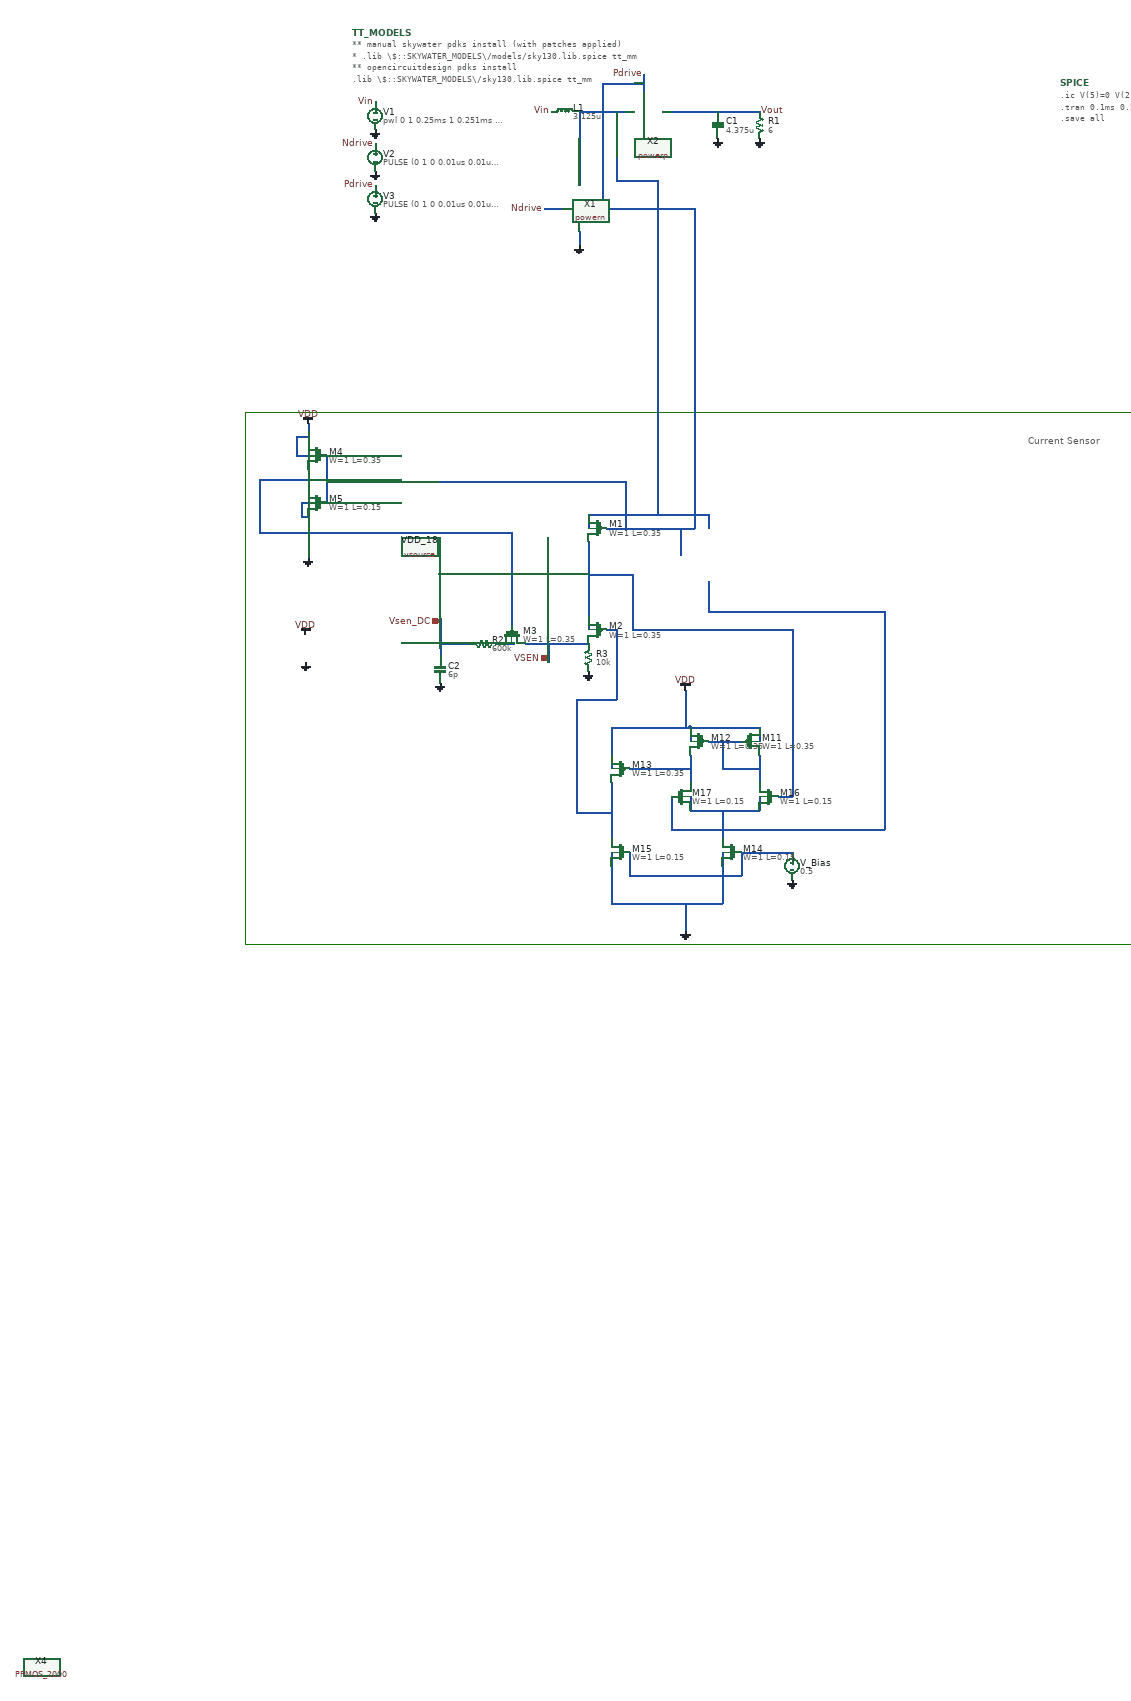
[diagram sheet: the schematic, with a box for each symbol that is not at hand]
v {xschem version=3.0.0 file_version=1.2 }
G {}
K {}
V {}
S {}
E {}
L 4 -330 1910 1650 1910 {}
L 4 1650 760 1650 1910 {}
L 4 -330 760 1650 760 {}
L 4 -330 760 -330 1910 {}
T {Current Sensor} 1360 810 0 0 0.6 0.6 {}
N 390 110 390 210 { lab=#net1}
N 690 110 780 110 { lab=Vout}
N 390 210 390 270 { lab=#net1}
N 390 110 490 110 { lab=#net1}
N 570 110 690 110 { lab=Vout}
N 390 370 390 400 { lab=GND}
N 530 30 530 70 { lab=Pdrive}
N 315 320 355 320 { lab=Ndrive}
N 440 50 530 50 { lab=Pdrive}
N 440 50 440 320 { lab=Pdrive}
N 440 320 550 320 { lab=Pdrive}
N 470 110 470 260 { lab=#net1}
N 470 260 550 260 { lab=#net1}
N 410 1040 410 1140 { lab=#net2}
N 450 1010 640 1010 { lab=Pdrive}
N 410 1140 410 1185 { lab=#net2}
N 410 1185 410 1200 { lab=#net2}
N 450 1230 455 1230 { lab=#net3}
N 275 1260 410 1260 { lab=VSEN}
N 90 1265 90 1285 { lab=Vsen_DC}
N 90 1260 155 1260 { lab=Vsen_DC}
N 90 1260 90 1270 { lab=Vsen_DC}
N 90 1205 90 1265 { lab=Vsen_DC}
N 325 1260 325 1300 { lab=VSEN}
N 490 910 490 1010 { lab=Pdrive}
N -155 910 490 910 { lab=Pdrive}
N -300 905 -195 905 { lab=#net4}
N -300 905 -300 1020 { lab=#net4}
N -300 1020 245 1020 { lab=#net4}
N 245 1020 245 1220 { lab=#net4}
N -195 985 -195 1075 { lab=GND}
N 670 1125 670 1190 { lab=#net5}
N 640 740 640 1010 { lab=Pdrive}
N 410 980 410 1010 { lab=#net1}
N 410 1200 410 1230 { lab=#net2}
N 210 1260 250 1260 { lab=#net6}
N -210 955 -192.5 955 { lab=GND}
N -210 955 -210 985 { lab=GND}
N -210 985 -195 985 { lab=GND}
N -220 852.5 -190 852.5 { lab=VDD}
N -220 812.5 -220 852.5 { lab=VDD}
N -220 812.5 -195 812.5 { lab=VDD}
N -195 882.5 -195 925 { lab=#net4}
N -155 852.5 -155 955 { lab=Pdrive}
N -195 785 -195 812.5 { lab=VDD}
N -195 802.5 -195 822.5 { lab=VDD}
N 610 1010 610 1070 { lab=Pdrive}
N 410 980 670 980 { lab=#net1}
N 670 980 670 1010 { lab=#net1}
N 560 380 560 980 { lab=#net1}
N 640 320 640 740 { lab=Pdrive}
N 550 320 640 320 { lab=Pdrive}
N 560 260 560 380 { lab=#net1}
N 550 260 560 260 { lab=#net1}
N 670 1470 740 1470 { lab=#net7}
N 630 1440 780 1440 { lab=VDD}
N 780 1500 780 1560 { lab=#net7}
N 630 1500 630 1560 { lab=#net8}
N 630 1620 780 1620 { lab=#net9}
N 700 1530 780 1530 { lab=#net7}
N 700 1470 700 1530 { lab=#net7}
N 700 1620 700 1680 { lab=#net9}
N 460 1440 630 1440 { lab=VDD}
N 460 1440 460 1500 { lab=VDD}
N 500 1530 630 1530 { lab=#net8}
N 460 1560 460 1680 { lab=#net3}
N 740 1710 740 1760 { lab=#net10}
N 500 1760 740 1760 { lab=#net10}
N 500 1710 500 1760 { lab=#net10}
N 740 1710 820 1710 { lab=#net10}
N 620 1360 620 1440 { lab=VDD}
N 700 1740 700 1820 { lab=GND}
N 460 1820 700 1820 { lab=GND}
N 460 1740 460 1820 { lab=GND}
N 620 1820 620 1880 { lab=GND}
N 820 1710 850 1710 { lab=#net10}
N 590 1590 590 1660 { lab=#net5}
N 590 1660 820 1660 { lab=#net5}
N 820 1660 850 1660 { lab=#net5}
N 820 1590 850 1590 { lab=#net2}
N 780 1440 780 1470 { lab=VDD}
N 630 1440 630 1470 { lab=VDD}
N 460 1710 460 1740 { lab=GND}
N 700 1710 700 1740 { lab=GND}
N 780 1590 780 1620 { lab=#net9}
N 630 1590 630 1620 { lab=#net9}
N 385 1625 460 1625 { lab=#net3}
N 460 1500 460 1530 { lab=VDD}
N 850 1660 1050 1660 { lab=#net5}
N 1050 1190 1050 1660 { lab=#net5}
N 670 1190 1050 1190 { lab=#net5}
N 850 1230 850 1590 { lab=#net2}
N 385 1380 385 1625 { lab=#net3}
N 385 1380 470 1380 { lab=#net3}
N 470 1230 470 1380 { lab=#net3}
N 455 1230 470 1230 { lab=#net3}
N 505 1230 850 1230 { lab=#net2}
N 505 1110 505 1230 { lab=#net2}
N 410 1110 505 1110 { lab=#net2}
C {devices/code.sym} -100 -60 0 0 {name=TT_MODELS
only_toplevel=true
format="tcleval(@value )"
value="** manual skywater pdks install (with patches applied)
* .lib \\\\$::SKYWATER_MODELS\\\\/models/sky130.lib.spice tt_mm

** opencircuitdesign pdks install
.lib \\\\$::SKYWATER_MODELS\\\\/sky130.lib.spice tt_mm

"
spice_ignore=false}
C {devices/code_shown.sym} 1430 50 0 0 {name=SPICE only_toplevel=false value="
.ic V(5)=0 V(2)=0 V(7)=0
.tran 0.1ms 0.5ms
.save all"}
C {devices/capa.sym} 690 140 0 0 {name=C1
m=1
value=4.375u
footprint=1206
device="ceramic capacitor"}
C {devices/res.sym} 780 140 0 0 {name=R1
value=6
footprint=1206
device=resistor
m=1}
C {devices/gnd.sym} 390 400 0 0 {name=l1 lab=GND}
C {devices/gnd.sym} 690 170 0 0 {name=l2 lab=GND}
C {devices/gnd.sym} 780 170 0 0 {name=l3 lab=GND}
C {devices/ind.sym} 360 110 3 0 {name=L1
m=1
value=3.125u
footprint=1206
device=inductor}
C {devices/lab_pin.sym} 330 110 0 0 {name=l4 sig_type=std_logic lab=Vin}
C {devices/lab_pin.sym} 780 110 2 0 {name=l5 sig_type=std_logic lab=Vout
}
C {devices/lab_pin.sym} 315 320 0 0 {name=l6 sig_type=std_logic lab=Ndrive}
C {devices/lab_pin.sym} 530 30 1 0 {name=l7 sig_type=std_logic lab=Pdrive}
C {devices/gnd.sym} -50 330 0 0 {name=l8 lab=GND}
C {devices/gnd.sym} -50 240 0 0 {name=l9 lab=GND}
C {devices/gnd.sym} -50 150 0 0 {name=l10 lab=GND}
C {devices/lab_pin.sym} -50 90 0 0 {name=l11 sig_type=std_logic lab=Vin}
C {devices/lab_pin.sym} -50 180 0 0 {name=l12 sig_type=std_logic lab=Ndrive}
C {devices/lab_pin.sym} -50 270 0 0 {name=l13 sig_type=std_logic lab=Pdrive}
C {devices/vsource.sym} -50 120 0 0 {name=V1 value="pwl 0 1 0.25ms 1 0.251ms 1.2 0.500ms 1.2 0.501ms 1.4"}
C {devices/vsource.sym} -50 210 0 0 {name=V2 value= "PULSE (0 1 0 0.01us 0.01us 0.85us 1.25us)"}
C {devices/vsource.sym} -50 300 0 0 {name=V3 value= "PULSE (0 1 0 0.01us 0.01us 0.85us 1.25us)"}
C {powern.sym} 15 320 0 0 {name=X1}
C {powerp.sym} 530 -50 3 1 {name=X2}
C {devices/vsource.sym} 850 1740 0 0 {name=V_Bias value=0.5}
C {devices/gnd.sym} 850 1770 0 0 {name=l14 lab=GND}
C {sky130_fd_pr/pfet_01v8_lvt.sym} 430 1010 0 1 {name=M1
L=0.35
W=1
nf=1
mult=1
ad="'int((nf+1)/2) * W/nf * 0.29'" 
pd="'2*int((nf+1)/2) * (W/nf + 0.29)'"
as="'int((nf+2)/2) * W/nf * 0.29'" 
ps="'2*int((nf+2)/2) * (W/nf + 0.29)'"
nrd="'0.29 / W'" nrs="'0.29 / W'"
sa=0 sb=0 sd=0
model=pfet_01v8_lvt
spiceprefix=X
}
C {sky130_fd_pr/pfet_01v8_lvt.sym} 430 1230 0 1 {name=M2
L=0.35
W=1
nf=1
mult=1
ad="'int((nf+1)/2) * W/nf * 0.29'" 
pd="'2*int((nf+1)/2) * (W/nf + 0.29)'"
as="'int((nf+2)/2) * W/nf * 0.29'" 
ps="'2*int((nf+2)/2) * (W/nf + 0.29)'"
nrd="'0.29 / W'" nrs="'0.29 / W'"
sa=0 sb=0 sd=0
model=pfet_01v8_lvt
spiceprefix=X
}
C {devices/gnd.sym} 410 1320 0 0 {name=l15 lab=GND}
C {sky130_fd_pr/pfet_01v8_lvt.sym} 245 1240 3 1 {name=M3
L=0.35
W=1
nf=1
mult=1
ad="'int((nf+1)/2) * W/nf * 0.29'" 
pd="'2*int((nf+1)/2) * (W/nf + 0.29)'"
as="'int((nf+2)/2) * W/nf * 0.29'" 
ps="'2*int((nf+2)/2) * (W/nf + 0.29)'"
nrd="'0.29 / W'" nrs="'0.29 / W'"
sa=0 sb=0 sd=0
model=pfet_01v8_lvt
spiceprefix=X
}
C {devices/capa.sym} 90 1315 0 0 {name=C2
m=1
value=6p
footprint=1206
device="ceramic capacitor"}
C {devices/gnd.sym} 90 1345 0 0 {name=l16 lab=GND}
C {devices/iopin.sym} 90 1210 3 0 {name=p1 lab=Vsen_DC}
C {devices/iopin.sym} 325 1290 1 0 {name=p3 lab=VSEN}
C {devices/res.sym} 185 1260 1 0 {name=R2
value=600k
footprint=1206
device=resistor
m=1}
C {devices/res.sym} 410 1290 2 0 {name=R3
value=10k
footprint=1206
device=resistor
m=1}
C {sky130_fd_pr/pfet_01v8_lvt.sym} -175 852.5 0 1 {name=M4
L=0.35
W=1
nf=1
mult=1
ad="'int((nf+1)/2) * W/nf * 0.29'" 
pd="'2*int((nf+1)/2) * (W/nf + 0.29)'"
as="'int((nf+2)/2) * W/nf * 0.29'" 
ps="'2*int((nf+2)/2) * (W/nf + 0.29)'"
nrd="'0.29 / W'" nrs="'0.29 / W'"
sa=0 sb=0 sd=0
model=pfet_01v8_lvt
spiceprefix=X
}
C {sky130_fd_pr/nfet_01v8_lvt.sym} -175 955 0 1 {name=M5
L=0.15
W=1
nf=1
mult=1
ad="'int((nf+1)/2) * W/nf * 0.29'" 
pd="'2*int((nf+1)/2) * (W/nf + 0.29)'"
as="'int((nf+2)/2) * W/nf * 0.29'" 
ps="'2*int((nf+2)/2) * (W/nf + 0.29)'"
nrd="'0.29 / W'" nrs="'0.29 / W'"
sa=0 sb=0 sd=0
model=nfet_01v8_lvt
spiceprefix=X
}
C {devices/gnd.sym} -195 1075 0 0 {name=l17 lab=GND}
C {devices/vdd.sym} -195 785 0 0 {name=l18 lab=VDD}
C {devices/vsource.sym} -200 1270 0 0 {name=VDD_18 value=1.8}
C {devices/vdd.sym} -200 1240 0 0 {name=l19 lab=VDD}
C {devices/gnd.sym} -200 1300 0 0 {name=l20 lab=GND}
C {PPMOS_2000.sym} -770 3470 0 0 {name=X4}
C {devices/vdd.sym} 620 1360 0 1 {name=l28 lab=VDD}
C {devices/gnd.sym} 620 1880 0 1 {name=l29 lab=GND}
C {sky130_fd_pr/pfet_01v8_lvt.sym} 760 1470 0 0 {name=M11
L=0.35
W=1
nf=1
mult=1
ad="'int((nf+1)/2) * W/nf * 0.29'" 
pd="'2*int((nf+1)/2) * (W/nf + 0.29)'"
as="'int((nf+2)/2) * W/nf * 0.29'" 
ps="'2*int((nf+2)/2) * (W/nf + 0.29)'"
nrd="'0.29 / W'" nrs="'0.29 / W'"
sa=0 sb=0 sd=0
model=pfet_01v8_lvt
spiceprefix=X
}
C {sky130_fd_pr/pfet_01v8_lvt.sym} 650 1470 0 1 {name=M12
L=0.35
W=1
nf=1
mult=1
ad="'int((nf+1)/2) * W/nf * 0.29'" 
pd="'2*int((nf+1)/2) * (W/nf + 0.29)'"
as="'int((nf+2)/2) * W/nf * 0.29'" 
ps="'2*int((nf+2)/2) * (W/nf + 0.29)'"
nrd="'0.29 / W'" nrs="'0.29 / W'"
sa=0 sb=0 sd=0
model=pfet_01v8_lvt
spiceprefix=X
}
C {sky130_fd_pr/pfet_01v8_lvt.sym} 480 1530 0 1 {name=M13
L=0.35
W=1
nf=1
mult=1
ad="'int((nf+1)/2) * W/nf * 0.29'" 
pd="'2*int((nf+1)/2) * (W/nf + 0.29)'"
as="'int((nf+2)/2) * W/nf * 0.29'" 
ps="'2*int((nf+2)/2) * (W/nf + 0.29)'"
nrd="'0.29 / W'" nrs="'0.29 / W'"
sa=0 sb=0 sd=0
model=pfet_01v8_lvt
spiceprefix=X
}
C {sky130_fd_pr/nfet_01v8_lvt.sym} 720 1710 0 1 {name=M14
L=0.15
W=1
nf=1
mult=1
ad="'int((nf+1)/2) * W/nf * 0.29'" 
pd="'2*int((nf+1)/2) * (W/nf + 0.29)'"
as="'int((nf+2)/2) * W/nf * 0.29'" 
ps="'2*int((nf+2)/2) * (W/nf + 0.29)'"
nrd="'0.29 / W'" nrs="'0.29 / W'"
sa=0 sb=0 sd=0
model=nfet_01v8_lvt
spiceprefix=X
}
C {sky130_fd_pr/nfet_01v8_lvt.sym} 480 1710 0 1 {name=M15
L=0.15
W=1
nf=1
mult=1
ad="'int((nf+1)/2) * W/nf * 0.29'" 
pd="'2*int((nf+1)/2) * (W/nf + 0.29)'"
as="'int((nf+2)/2) * W/nf * 0.29'" 
ps="'2*int((nf+2)/2) * (W/nf + 0.29)'"
nrd="'0.29 / W'" nrs="'0.29 / W'"
sa=0 sb=0 sd=0
model=nfet_01v8_lvt
spiceprefix=X
}
C {sky130_fd_pr/nfet_01v8_lvt.sym} 800 1590 0 1 {name=M16
L=0.15
W=1
nf=1
mult=1
ad="'int((nf+1)/2) * W/nf * 0.29'" 
pd="'2*int((nf+1)/2) * (W/nf + 0.29)'"
as="'int((nf+2)/2) * W/nf * 0.29'" 
ps="'2*int((nf+2)/2) * (W/nf + 0.29)'"
nrd="'0.29 / W'" nrs="'0.29 / W'"
sa=0 sb=0 sd=0
model=nfet_01v8_lvt
spiceprefix=X
}
C {sky130_fd_pr/nfet_01v8_lvt.sym} 610 1590 0 0 {name=M17
L=0.15
W=1
nf=1
mult=1
ad="'int((nf+1)/2) * W/nf * 0.29'" 
pd="'2*int((nf+1)/2) * (W/nf + 0.29)'"
as="'int((nf+2)/2) * W/nf * 0.29'" 
ps="'2*int((nf+2)/2) * (W/nf + 0.29)'"
nrd="'0.29 / W'" nrs="'0.29 / W'"
sa=0 sb=0 sd=0
model=nfet_01v8_lvt
spiceprefix=X
}
